# OpenTallas memory compiler (tools/mem_compiler), ASAP7 abstract view
VERSION 5.7 ;
BUSBITCHARS "[]" ;
DIVIDERCHAR "/" ;
PROPERTYDEFINITIONS
  MACRO width INTEGER ;
  MACRO depth INTEGER ;
  MACRO banks INTEGER ;
END PROPERTYDEFINITIONS
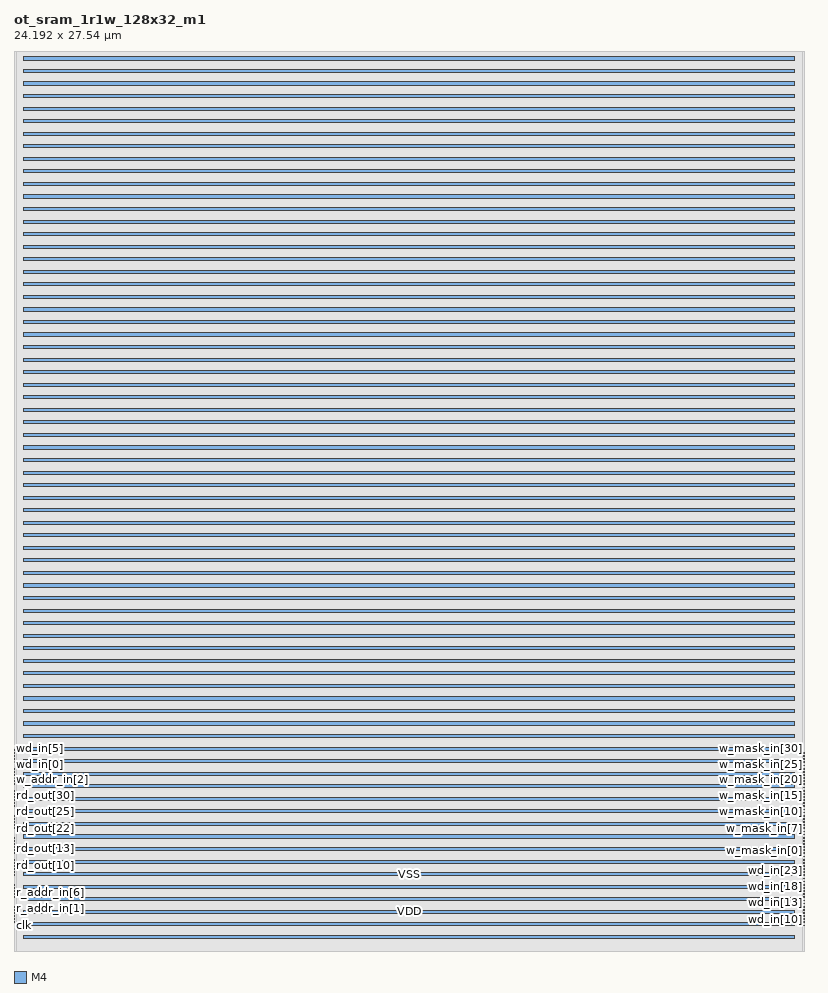
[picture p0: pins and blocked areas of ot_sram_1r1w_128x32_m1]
MACRO ot_sram_1r1w_128x32_m1
  PROPERTY width 32 ;
  PROPERTY depth 128 ;
  PROPERTY banks 1 ;
  FOREIGN ot_sram_1r1w_128x32_m1 0 0 ;
  SYMMETRY X Y R90 ;
  SIZE 24.192 BY 27.540 ;
  CLASS BLOCK ;
  PIN clk
    DIRECTION INPUT ;
    USE CLOCK ;
    SHAPE ABUTMENT ;
    PORT
      LAYER M4 ;
      RECT 0.000 0.768 0.024 0.792 ;
    END
  END clk
  PIN r_ce_in
    DIRECTION INPUT ;
    USE SIGNAL ;
    SHAPE ABUTMENT ;
    PORT
      LAYER M4 ;
      RECT 0.000 0.864 0.024 0.888 ;
    END
  END r_ce_in
  PIN r_addr_in[0]
    DIRECTION INPUT ;
    USE SIGNAL ;
    SHAPE ABUTMENT ;
    PORT
      LAYER M4 ;
      RECT 0.000 0.960 0.024 0.984 ;
    END
  END r_addr_in[0]
  PIN r_addr_in[1]
    DIRECTION INPUT ;
    USE SIGNAL ;
    SHAPE ABUTMENT ;
    PORT
      LAYER M4 ;
      RECT 0.000 1.056 0.024 1.080 ;
    END
  END r_addr_in[1]
  PIN r_addr_in[2]
    DIRECTION INPUT ;
    USE SIGNAL ;
    SHAPE ABUTMENT ;
    PORT
      LAYER M4 ;
      RECT 0.000 1.152 0.024 1.176 ;
    END
  END r_addr_in[2]
  PIN r_addr_in[3]
    DIRECTION INPUT ;
    USE SIGNAL ;
    SHAPE ABUTMENT ;
    PORT
      LAYER M4 ;
      RECT 0.000 1.248 0.024 1.272 ;
    END
  END r_addr_in[3]
  PIN r_addr_in[4]
    DIRECTION INPUT ;
    USE SIGNAL ;
    SHAPE ABUTMENT ;
    PORT
      LAYER M4 ;
      RECT 0.000 1.344 0.024 1.368 ;
    END
  END r_addr_in[4]
  PIN r_addr_in[5]
    DIRECTION INPUT ;
    USE SIGNAL ;
    SHAPE ABUTMENT ;
    PORT
      LAYER M4 ;
      RECT 0.000 1.440 0.024 1.464 ;
    END
  END r_addr_in[5]
  PIN r_addr_in[6]
    DIRECTION INPUT ;
    USE SIGNAL ;
    SHAPE ABUTMENT ;
    PORT
      LAYER M4 ;
      RECT 0.000 1.536 0.024 1.560 ;
    END
  END r_addr_in[6]
  PIN rd_out[0]
    DIRECTION OUTPUT ;
    USE SIGNAL ;
    SHAPE ABUTMENT ;
    PORT
      LAYER M4 ;
      RECT 0.000 1.632 0.024 1.656 ;
    END
  END rd_out[0]
  PIN rd_out[1]
    DIRECTION OUTPUT ;
    USE SIGNAL ;
    SHAPE ABUTMENT ;
    PORT
      LAYER M4 ;
      RECT 0.000 1.728 0.024 1.752 ;
    END
  END rd_out[1]
  PIN rd_out[2]
    DIRECTION OUTPUT ;
    USE SIGNAL ;
    SHAPE ABUTMENT ;
    PORT
      LAYER M4 ;
      RECT 0.000 1.824 0.024 1.848 ;
    END
  END rd_out[2]
  PIN rd_out[3]
    DIRECTION OUTPUT ;
    USE SIGNAL ;
    SHAPE ABUTMENT ;
    PORT
      LAYER M4 ;
      RECT 0.000 1.920 0.024 1.944 ;
    END
  END rd_out[3]
  PIN rd_out[4]
    DIRECTION OUTPUT ;
    USE SIGNAL ;
    SHAPE ABUTMENT ;
    PORT
      LAYER M4 ;
      RECT 0.000 2.016 0.024 2.040 ;
    END
  END rd_out[4]
  PIN rd_out[5]
    DIRECTION OUTPUT ;
    USE SIGNAL ;
    SHAPE ABUTMENT ;
    PORT
      LAYER M4 ;
      RECT 0.000 2.112 0.024 2.136 ;
    END
  END rd_out[5]
  PIN rd_out[6]
    DIRECTION OUTPUT ;
    USE SIGNAL ;
    SHAPE ABUTMENT ;
    PORT
      LAYER M4 ;
      RECT 0.000 2.208 0.024 2.232 ;
    END
  END rd_out[6]
  PIN rd_out[7]
    DIRECTION OUTPUT ;
    USE SIGNAL ;
    SHAPE ABUTMENT ;
    PORT
      LAYER M4 ;
      RECT 0.000 2.304 0.024 2.328 ;
    END
  END rd_out[7]
  PIN rd_out[8]
    DIRECTION OUTPUT ;
    USE SIGNAL ;
    SHAPE ABUTMENT ;
    PORT
      LAYER M4 ;
      RECT 0.000 2.400 0.024 2.424 ;
    END
  END rd_out[8]
  PIN rd_out[9]
    DIRECTION OUTPUT ;
    USE SIGNAL ;
    SHAPE ABUTMENT ;
    PORT
      LAYER M4 ;
      RECT 0.000 2.496 0.024 2.520 ;
    END
  END rd_out[9]
  PIN rd_out[10]
    DIRECTION OUTPUT ;
    USE SIGNAL ;
    SHAPE ABUTMENT ;
    PORT
      LAYER M4 ;
      RECT 0.000 2.592 0.024 2.616 ;
    END
  END rd_out[10]
  PIN rd_out[11]
    DIRECTION OUTPUT ;
    USE SIGNAL ;
    SHAPE ABUTMENT ;
    PORT
      LAYER M4 ;
      RECT 0.000 2.688 0.024 2.712 ;
    END
  END rd_out[11]
  PIN rd_out[12]
    DIRECTION OUTPUT ;
    USE SIGNAL ;
    SHAPE ABUTMENT ;
    PORT
      LAYER M4 ;
      RECT 0.000 2.784 0.024 2.808 ;
    END
  END rd_out[12]
  PIN rd_out[13]
    DIRECTION OUTPUT ;
    USE SIGNAL ;
    SHAPE ABUTMENT ;
    PORT
      LAYER M4 ;
      RECT 0.000 2.880 0.024 2.904 ;
    END
  END rd_out[13]
  PIN rd_out[14]
    DIRECTION OUTPUT ;
    USE SIGNAL ;
    SHAPE ABUTMENT ;
    PORT
      LAYER M4 ;
      RECT 0.000 2.976 0.024 3.000 ;
    END
  END rd_out[14]
  PIN rd_out[15]
    DIRECTION OUTPUT ;
    USE SIGNAL ;
    SHAPE ABUTMENT ;
    PORT
      LAYER M4 ;
      RECT 0.000 3.072 0.024 3.096 ;
    END
  END rd_out[15]
  PIN rd_out[16]
    DIRECTION OUTPUT ;
    USE SIGNAL ;
    SHAPE ABUTMENT ;
    PORT
      LAYER M4 ;
      RECT 0.000 3.168 0.024 3.192 ;
    END
  END rd_out[16]
  PIN rd_out[17]
    DIRECTION OUTPUT ;
    USE SIGNAL ;
    SHAPE ABUTMENT ;
    PORT
      LAYER M4 ;
      RECT 0.000 3.264 0.024 3.288 ;
    END
  END rd_out[17]
  PIN rd_out[18]
    DIRECTION OUTPUT ;
    USE SIGNAL ;
    SHAPE ABUTMENT ;
    PORT
      LAYER M4 ;
      RECT 0.000 3.360 0.024 3.384 ;
    END
  END rd_out[18]
  PIN rd_out[19]
    DIRECTION OUTPUT ;
    USE SIGNAL ;
    SHAPE ABUTMENT ;
    PORT
      LAYER M4 ;
      RECT 0.000 3.456 0.024 3.480 ;
    END
  END rd_out[19]
  PIN rd_out[20]
    DIRECTION OUTPUT ;
    USE SIGNAL ;
    SHAPE ABUTMENT ;
    PORT
      LAYER M4 ;
      RECT 0.000 3.552 0.024 3.576 ;
    END
  END rd_out[20]
  PIN rd_out[21]
    DIRECTION OUTPUT ;
    USE SIGNAL ;
    SHAPE ABUTMENT ;
    PORT
      LAYER M4 ;
      RECT 0.000 3.648 0.024 3.672 ;
    END
  END rd_out[21]
  PIN rd_out[22]
    DIRECTION OUTPUT ;
    USE SIGNAL ;
    SHAPE ABUTMENT ;
    PORT
      LAYER M4 ;
      RECT 0.000 3.744 0.024 3.768 ;
    END
  END rd_out[22]
  PIN rd_out[23]
    DIRECTION OUTPUT ;
    USE SIGNAL ;
    SHAPE ABUTMENT ;
    PORT
      LAYER M4 ;
      RECT 0.000 3.840 0.024 3.864 ;
    END
  END rd_out[23]
  PIN rd_out[24]
    DIRECTION OUTPUT ;
    USE SIGNAL ;
    SHAPE ABUTMENT ;
    PORT
      LAYER M4 ;
      RECT 0.000 3.936 0.024 3.960 ;
    END
  END rd_out[24]
  PIN rd_out[25]
    DIRECTION OUTPUT ;
    USE SIGNAL ;
    SHAPE ABUTMENT ;
    PORT
      LAYER M4 ;
      RECT 0.000 4.032 0.024 4.056 ;
    END
  END rd_out[25]
  PIN rd_out[26]
    DIRECTION OUTPUT ;
    USE SIGNAL ;
    SHAPE ABUTMENT ;
    PORT
      LAYER M4 ;
      RECT 0.000 4.128 0.024 4.152 ;
    END
  END rd_out[26]
  PIN rd_out[27]
    DIRECTION OUTPUT ;
    USE SIGNAL ;
    SHAPE ABUTMENT ;
    PORT
      LAYER M4 ;
      RECT 0.000 4.224 0.024 4.248 ;
    END
  END rd_out[27]
  PIN rd_out[28]
    DIRECTION OUTPUT ;
    USE SIGNAL ;
    SHAPE ABUTMENT ;
    PORT
      LAYER M4 ;
      RECT 0.000 4.320 0.024 4.344 ;
    END
  END rd_out[28]
  PIN rd_out[29]
    DIRECTION OUTPUT ;
    USE SIGNAL ;
    SHAPE ABUTMENT ;
    PORT
      LAYER M4 ;
      RECT 0.000 4.416 0.024 4.440 ;
    END
  END rd_out[29]
  PIN rd_out[30]
    DIRECTION OUTPUT ;
    USE SIGNAL ;
    SHAPE ABUTMENT ;
    PORT
      LAYER M4 ;
      RECT 0.000 4.512 0.024 4.536 ;
    END
  END rd_out[30]
  PIN rd_out[31]
    DIRECTION OUTPUT ;
    USE SIGNAL ;
    SHAPE ABUTMENT ;
    PORT
      LAYER M4 ;
      RECT 0.000 4.608 0.024 4.632 ;
    END
  END rd_out[31]
  PIN w_ce_in
    DIRECTION INPUT ;
    USE SIGNAL ;
    SHAPE ABUTMENT ;
    PORT
      LAYER M4 ;
      RECT 0.000 4.704 0.024 4.728 ;
    END
  END w_ce_in
  PIN w_addr_in[0]
    DIRECTION INPUT ;
    USE SIGNAL ;
    SHAPE ABUTMENT ;
    PORT
      LAYER M4 ;
      RECT 0.000 4.800 0.024 4.824 ;
    END
  END w_addr_in[0]
  PIN w_addr_in[1]
    DIRECTION INPUT ;
    USE SIGNAL ;
    SHAPE ABUTMENT ;
    PORT
      LAYER M4 ;
      RECT 0.000 4.896 0.024 4.920 ;
    END
  END w_addr_in[1]
  PIN w_addr_in[2]
    DIRECTION INPUT ;
    USE SIGNAL ;
    SHAPE ABUTMENT ;
    PORT
      LAYER M4 ;
      RECT 0.000 4.992 0.024 5.016 ;
    END
  END w_addr_in[2]
  PIN w_addr_in[3]
    DIRECTION INPUT ;
    USE SIGNAL ;
    SHAPE ABUTMENT ;
    PORT
      LAYER M4 ;
      RECT 0.000 5.088 0.024 5.112 ;
    END
  END w_addr_in[3]
  PIN w_addr_in[4]
    DIRECTION INPUT ;
    USE SIGNAL ;
    SHAPE ABUTMENT ;
    PORT
      LAYER M4 ;
      RECT 0.000 5.184 0.024 5.208 ;
    END
  END w_addr_in[4]
  PIN w_addr_in[5]
    DIRECTION INPUT ;
    USE SIGNAL ;
    SHAPE ABUTMENT ;
    PORT
      LAYER M4 ;
      RECT 0.000 5.280 0.024 5.304 ;
    END
  END w_addr_in[5]
  PIN w_addr_in[6]
    DIRECTION INPUT ;
    USE SIGNAL ;
    SHAPE ABUTMENT ;
    PORT
      LAYER M4 ;
      RECT 0.000 5.376 0.024 5.400 ;
    END
  END w_addr_in[6]
  PIN wd_in[0]
    DIRECTION INPUT ;
    USE SIGNAL ;
    SHAPE ABUTMENT ;
    PORT
      LAYER M4 ;
      RECT 0.000 5.472 0.024 5.496 ;
    END
  END wd_in[0]
  PIN wd_in[1]
    DIRECTION INPUT ;
    USE SIGNAL ;
    SHAPE ABUTMENT ;
    PORT
      LAYER M4 ;
      RECT 0.000 5.568 0.024 5.592 ;
    END
  END wd_in[1]
  PIN wd_in[2]
    DIRECTION INPUT ;
    USE SIGNAL ;
    SHAPE ABUTMENT ;
    PORT
      LAYER M4 ;
      RECT 0.000 5.664 0.024 5.688 ;
    END
  END wd_in[2]
  PIN wd_in[3]
    DIRECTION INPUT ;
    USE SIGNAL ;
    SHAPE ABUTMENT ;
    PORT
      LAYER M4 ;
      RECT 0.000 5.760 0.024 5.784 ;
    END
  END wd_in[3]
  PIN wd_in[4]
    DIRECTION INPUT ;
    USE SIGNAL ;
    SHAPE ABUTMENT ;
    PORT
      LAYER M4 ;
      RECT 0.000 5.856 0.024 5.880 ;
    END
  END wd_in[4]
  PIN wd_in[5]
    DIRECTION INPUT ;
    USE SIGNAL ;
    SHAPE ABUTMENT ;
    PORT
      LAYER M4 ;
      RECT 0.000 5.952 0.024 5.976 ;
    END
  END wd_in[5]
  PIN wd_in[6]
    DIRECTION INPUT ;
    USE SIGNAL ;
    SHAPE ABUTMENT ;
    PORT
      LAYER M4 ;
      RECT 0.000 6.048 0.024 6.072 ;
    END
  END wd_in[6]
  PIN wd_in[7]
    DIRECTION INPUT ;
    USE SIGNAL ;
    SHAPE ABUTMENT ;
    PORT
      LAYER M4 ;
      RECT 0.000 6.144 0.024 6.168 ;
    END
  END wd_in[7]
  PIN wd_in[8]
    DIRECTION INPUT ;
    USE SIGNAL ;
    SHAPE ABUTMENT ;
    PORT
      LAYER M4 ;
      RECT 24.168 0.768 24.192 0.792 ;
    END
  END wd_in[8]
  PIN wd_in[9]
    DIRECTION INPUT ;
    USE SIGNAL ;
    SHAPE ABUTMENT ;
    PORT
      LAYER M4 ;
      RECT 24.168 0.864 24.192 0.888 ;
    END
  END wd_in[9]
  PIN wd_in[10]
    DIRECTION INPUT ;
    USE SIGNAL ;
    SHAPE ABUTMENT ;
    PORT
      LAYER M4 ;
      RECT 24.168 0.960 24.192 0.984 ;
    END
  END wd_in[10]
  PIN wd_in[11]
    DIRECTION INPUT ;
    USE SIGNAL ;
    SHAPE ABUTMENT ;
    PORT
      LAYER M4 ;
      RECT 24.168 1.056 24.192 1.080 ;
    END
  END wd_in[11]
  PIN wd_in[12]
    DIRECTION INPUT ;
    USE SIGNAL ;
    SHAPE ABUTMENT ;
    PORT
      LAYER M4 ;
      RECT 24.168 1.152 24.192 1.176 ;
    END
  END wd_in[12]
  PIN wd_in[13]
    DIRECTION INPUT ;
    USE SIGNAL ;
    SHAPE ABUTMENT ;
    PORT
      LAYER M4 ;
      RECT 24.168 1.248 24.192 1.272 ;
    END
  END wd_in[13]
  PIN wd_in[14]
    DIRECTION INPUT ;
    USE SIGNAL ;
    SHAPE ABUTMENT ;
    PORT
      LAYER M4 ;
      RECT 24.168 1.344 24.192 1.368 ;
    END
  END wd_in[14]
  PIN wd_in[15]
    DIRECTION INPUT ;
    USE SIGNAL ;
    SHAPE ABUTMENT ;
    PORT
      LAYER M4 ;
      RECT 24.168 1.440 24.192 1.464 ;
    END
  END wd_in[15]
  PIN wd_in[16]
    DIRECTION INPUT ;
    USE SIGNAL ;
    SHAPE ABUTMENT ;
    PORT
      LAYER M4 ;
      RECT 24.168 1.536 24.192 1.560 ;
    END
  END wd_in[16]
  PIN wd_in[17]
    DIRECTION INPUT ;
    USE SIGNAL ;
    SHAPE ABUTMENT ;
    PORT
      LAYER M4 ;
      RECT 24.168 1.632 24.192 1.656 ;
    END
  END wd_in[17]
  PIN wd_in[18]
    DIRECTION INPUT ;
    USE SIGNAL ;
    SHAPE ABUTMENT ;
    PORT
      LAYER M4 ;
      RECT 24.168 1.728 24.192 1.752 ;
    END
  END wd_in[18]
  PIN wd_in[19]
    DIRECTION INPUT ;
    USE SIGNAL ;
    SHAPE ABUTMENT ;
    PORT
      LAYER M4 ;
      RECT 24.168 1.824 24.192 1.848 ;
    END
  END wd_in[19]
  PIN wd_in[20]
    DIRECTION INPUT ;
    USE SIGNAL ;
    SHAPE ABUTMENT ;
    PORT
      LAYER M4 ;
      RECT 24.168 1.920 24.192 1.944 ;
    END
  END wd_in[20]
  PIN wd_in[21]
    DIRECTION INPUT ;
    USE SIGNAL ;
    SHAPE ABUTMENT ;
    PORT
      LAYER M4 ;
      RECT 24.168 2.016 24.192 2.040 ;
    END
  END wd_in[21]
  PIN wd_in[22]
    DIRECTION INPUT ;
    USE SIGNAL ;
    SHAPE ABUTMENT ;
    PORT
      LAYER M4 ;
      RECT 24.168 2.112 24.192 2.136 ;
    END
  END wd_in[22]
  PIN wd_in[23]
    DIRECTION INPUT ;
    USE SIGNAL ;
    SHAPE ABUTMENT ;
    PORT
      LAYER M4 ;
      RECT 24.168 2.208 24.192 2.232 ;
    END
  END wd_in[23]
  PIN wd_in[24]
    DIRECTION INPUT ;
    USE SIGNAL ;
    SHAPE ABUTMENT ;
    PORT
      LAYER M4 ;
      RECT 24.168 2.304 24.192 2.328 ;
    END
  END wd_in[24]
  PIN wd_in[25]
    DIRECTION INPUT ;
    USE SIGNAL ;
    SHAPE ABUTMENT ;
    PORT
      LAYER M4 ;
      RECT 24.168 2.400 24.192 2.424 ;
    END
  END wd_in[25]
  PIN wd_in[26]
    DIRECTION INPUT ;
    USE SIGNAL ;
    SHAPE ABUTMENT ;
    PORT
      LAYER M4 ;
      RECT 24.168 2.496 24.192 2.520 ;
    END
  END wd_in[26]
  PIN wd_in[27]
    DIRECTION INPUT ;
    USE SIGNAL ;
    SHAPE ABUTMENT ;
    PORT
      LAYER M4 ;
      RECT 24.168 2.592 24.192 2.616 ;
    END
  END wd_in[27]
  PIN wd_in[28]
    DIRECTION INPUT ;
    USE SIGNAL ;
    SHAPE ABUTMENT ;
    PORT
      LAYER M4 ;
      RECT 24.168 2.688 24.192 2.712 ;
    END
  END wd_in[28]
  PIN wd_in[29]
    DIRECTION INPUT ;
    USE SIGNAL ;
    SHAPE ABUTMENT ;
    PORT
      LAYER M4 ;
      RECT 24.168 2.784 24.192 2.808 ;
    END
  END wd_in[29]
  PIN wd_in[30]
    DIRECTION INPUT ;
    USE SIGNAL ;
    SHAPE ABUTMENT ;
    PORT
      LAYER M4 ;
      RECT 24.168 2.880 24.192 2.904 ;
    END
  END wd_in[30]
  PIN wd_in[31]
    DIRECTION INPUT ;
    USE SIGNAL ;
    SHAPE ABUTMENT ;
    PORT
      LAYER M4 ;
      RECT 24.168 2.976 24.192 3.000 ;
    END
  END wd_in[31]
  PIN w_mask_in[0]
    DIRECTION INPUT ;
    USE SIGNAL ;
    SHAPE ABUTMENT ;
    PORT
      LAYER M4 ;
      RECT 24.168 3.072 24.192 3.096 ;
    END
  END w_mask_in[0]
  PIN w_mask_in[1]
    DIRECTION INPUT ;
    USE SIGNAL ;
    SHAPE ABUTMENT ;
    PORT
      LAYER M4 ;
      RECT 24.168 3.168 24.192 3.192 ;
    END
  END w_mask_in[1]
  PIN w_mask_in[2]
    DIRECTION INPUT ;
    USE SIGNAL ;
    SHAPE ABUTMENT ;
    PORT
      LAYER M4 ;
      RECT 24.168 3.264 24.192 3.288 ;
    END
  END w_mask_in[2]
  PIN w_mask_in[3]
    DIRECTION INPUT ;
    USE SIGNAL ;
    SHAPE ABUTMENT ;
    PORT
      LAYER M4 ;
      RECT 24.168 3.360 24.192 3.384 ;
    END
  END w_mask_in[3]
  PIN w_mask_in[4]
    DIRECTION INPUT ;
    USE SIGNAL ;
    SHAPE ABUTMENT ;
    PORT
      LAYER M4 ;
      RECT 24.168 3.456 24.192 3.480 ;
    END
  END w_mask_in[4]
  PIN w_mask_in[5]
    DIRECTION INPUT ;
    USE SIGNAL ;
    SHAPE ABUTMENT ;
    PORT
      LAYER M4 ;
      RECT 24.168 3.552 24.192 3.576 ;
    END
  END w_mask_in[5]
  PIN w_mask_in[6]
    DIRECTION INPUT ;
    USE SIGNAL ;
    SHAPE ABUTMENT ;
    PORT
      LAYER M4 ;
      RECT 24.168 3.648 24.192 3.672 ;
    END
  END w_mask_in[6]
  PIN w_mask_in[7]
    DIRECTION INPUT ;
    USE SIGNAL ;
    SHAPE ABUTMENT ;
    PORT
      LAYER M4 ;
      RECT 24.168 3.744 24.192 3.768 ;
    END
  END w_mask_in[7]
  PIN w_mask_in[8]
    DIRECTION INPUT ;
    USE SIGNAL ;
    SHAPE ABUTMENT ;
    PORT
      LAYER M4 ;
      RECT 24.168 3.840 24.192 3.864 ;
    END
  END w_mask_in[8]
  PIN w_mask_in[9]
    DIRECTION INPUT ;
    USE SIGNAL ;
    SHAPE ABUTMENT ;
    PORT
      LAYER M4 ;
      RECT 24.168 3.936 24.192 3.960 ;
    END
  END w_mask_in[9]
  PIN w_mask_in[10]
    DIRECTION INPUT ;
    USE SIGNAL ;
    SHAPE ABUTMENT ;
    PORT
      LAYER M4 ;
      RECT 24.168 4.032 24.192 4.056 ;
    END
  END w_mask_in[10]
  PIN w_mask_in[11]
    DIRECTION INPUT ;
    USE SIGNAL ;
    SHAPE ABUTMENT ;
    PORT
      LAYER M4 ;
      RECT 24.168 4.128 24.192 4.152 ;
    END
  END w_mask_in[11]
  PIN w_mask_in[12]
    DIRECTION INPUT ;
    USE SIGNAL ;
    SHAPE ABUTMENT ;
    PORT
      LAYER M4 ;
      RECT 24.168 4.224 24.192 4.248 ;
    END
  END w_mask_in[12]
  PIN w_mask_in[13]
    DIRECTION INPUT ;
    USE SIGNAL ;
    SHAPE ABUTMENT ;
    PORT
      LAYER M4 ;
      RECT 24.168 4.320 24.192 4.344 ;
    END
  END w_mask_in[13]
  PIN w_mask_in[14]
    DIRECTION INPUT ;
    USE SIGNAL ;
    SHAPE ABUTMENT ;
    PORT
      LAYER M4 ;
      RECT 24.168 4.416 24.192 4.440 ;
    END
  END w_mask_in[14]
  PIN w_mask_in[15]
    DIRECTION INPUT ;
    USE SIGNAL ;
    SHAPE ABUTMENT ;
    PORT
      LAYER M4 ;
      RECT 24.168 4.512 24.192 4.536 ;
    END
  END w_mask_in[15]
  PIN w_mask_in[16]
    DIRECTION INPUT ;
    USE SIGNAL ;
    SHAPE ABUTMENT ;
    PORT
      LAYER M4 ;
      RECT 24.168 4.608 24.192 4.632 ;
    END
  END w_mask_in[16]
  PIN w_mask_in[17]
    DIRECTION INPUT ;
    USE SIGNAL ;
    SHAPE ABUTMENT ;
    PORT
      LAYER M4 ;
      RECT 24.168 4.704 24.192 4.728 ;
    END
  END w_mask_in[17]
  PIN w_mask_in[18]
    DIRECTION INPUT ;
    USE SIGNAL ;
    SHAPE ABUTMENT ;
    PORT
      LAYER M4 ;
      RECT 24.168 4.800 24.192 4.824 ;
    END
  END w_mask_in[18]
  PIN w_mask_in[19]
    DIRECTION INPUT ;
    USE SIGNAL ;
    SHAPE ABUTMENT ;
    PORT
      LAYER M4 ;
      RECT 24.168 4.896 24.192 4.920 ;
    END
  END w_mask_in[19]
  PIN w_mask_in[20]
    DIRECTION INPUT ;
    USE SIGNAL ;
    SHAPE ABUTMENT ;
    PORT
      LAYER M4 ;
      RECT 24.168 4.992 24.192 5.016 ;
    END
  END w_mask_in[20]
  PIN w_mask_in[21]
    DIRECTION INPUT ;
    USE SIGNAL ;
    SHAPE ABUTMENT ;
    PORT
      LAYER M4 ;
      RECT 24.168 5.088 24.192 5.112 ;
    END
  END w_mask_in[21]
  PIN w_mask_in[22]
    DIRECTION INPUT ;
    USE SIGNAL ;
    SHAPE ABUTMENT ;
    PORT
      LAYER M4 ;
      RECT 24.168 5.184 24.192 5.208 ;
    END
  END w_mask_in[22]
  PIN w_mask_in[23]
    DIRECTION INPUT ;
    USE SIGNAL ;
    SHAPE ABUTMENT ;
    PORT
      LAYER M4 ;
      RECT 24.168 5.280 24.192 5.304 ;
    END
  END w_mask_in[23]
  PIN w_mask_in[24]
    DIRECTION INPUT ;
    USE SIGNAL ;
    SHAPE ABUTMENT ;
    PORT
      LAYER M4 ;
      RECT 24.168 5.376 24.192 5.400 ;
    END
  END w_mask_in[24]
  PIN w_mask_in[25]
    DIRECTION INPUT ;
    USE SIGNAL ;
    SHAPE ABUTMENT ;
    PORT
      LAYER M4 ;
      RECT 24.168 5.472 24.192 5.496 ;
    END
  END w_mask_in[25]
  PIN w_mask_in[26]
    DIRECTION INPUT ;
    USE SIGNAL ;
    SHAPE ABUTMENT ;
    PORT
      LAYER M4 ;
      RECT 24.168 5.568 24.192 5.592 ;
    END
  END w_mask_in[26]
  PIN w_mask_in[27]
    DIRECTION INPUT ;
    USE SIGNAL ;
    SHAPE ABUTMENT ;
    PORT
      LAYER M4 ;
      RECT 24.168 5.664 24.192 5.688 ;
    END
  END w_mask_in[27]
  PIN w_mask_in[28]
    DIRECTION INPUT ;
    USE SIGNAL ;
    SHAPE ABUTMENT ;
    PORT
      LAYER M4 ;
      RECT 24.168 5.760 24.192 5.784 ;
    END
  END w_mask_in[28]
  PIN w_mask_in[29]
    DIRECTION INPUT ;
    USE SIGNAL ;
    SHAPE ABUTMENT ;
    PORT
      LAYER M4 ;
      RECT 24.168 5.856 24.192 5.880 ;
    END
  END w_mask_in[29]
  PIN w_mask_in[30]
    DIRECTION INPUT ;
    USE SIGNAL ;
    SHAPE ABUTMENT ;
    PORT
      LAYER M4 ;
      RECT 24.168 5.952 24.192 5.976 ;
    END
  END w_mask_in[30]
  PIN w_mask_in[31]
    DIRECTION INPUT ;
    USE SIGNAL ;
    SHAPE ABUTMENT ;
    PORT
      LAYER M4 ;
      RECT 24.168 6.048 24.192 6.072 ;
    END
  END w_mask_in[31]
  PIN VDD
    DIRECTION INOUT ;
    USE POWER ;
    PORT
      LAYER M4 ;
      RECT 0.300 0.384 23.892 0.480 ;
      RECT 0.300 1.152 23.892 1.248 ;
      RECT 0.300 1.920 23.892 2.016 ;
      RECT 0.300 2.688 23.892 2.784 ;
      RECT 0.300 3.456 23.892 3.552 ;
      RECT 0.300 4.224 23.892 4.320 ;
      RECT 0.300 4.992 23.892 5.088 ;
      RECT 0.300 5.760 23.892 5.856 ;
      RECT 0.300 6.528 23.892 6.624 ;
      RECT 0.300 7.296 23.892 7.392 ;
      RECT 0.300 8.064 23.892 8.160 ;
      RECT 0.300 8.832 23.892 8.928 ;
      RECT 0.300 9.600 23.892 9.696 ;
      RECT 0.300 10.368 23.892 10.464 ;
      RECT 0.300 11.136 23.892 11.232 ;
      RECT 0.300 11.904 23.892 12.000 ;
      RECT 0.300 12.672 23.892 12.768 ;
      RECT 0.300 13.440 23.892 13.536 ;
      RECT 0.300 14.208 23.892 14.304 ;
      RECT 0.300 14.976 23.892 15.072 ;
      RECT 0.300 15.744 23.892 15.840 ;
      RECT 0.300 16.512 23.892 16.608 ;
      RECT 0.300 17.280 23.892 17.376 ;
      RECT 0.300 18.048 23.892 18.144 ;
      RECT 0.300 18.816 23.892 18.912 ;
      RECT 0.300 19.584 23.892 19.680 ;
      RECT 0.300 20.352 23.892 20.448 ;
      RECT 0.300 21.120 23.892 21.216 ;
      RECT 0.300 21.888 23.892 21.984 ;
      RECT 0.300 22.656 23.892 22.752 ;
      RECT 0.300 23.424 23.892 23.520 ;
      RECT 0.300 24.192 23.892 24.288 ;
      RECT 0.300 24.960 23.892 25.056 ;
      RECT 0.300 25.728 23.892 25.824 ;
      RECT 0.300 26.496 23.892 26.592 ;
      RECT 0.300 27.264 23.892 27.360 ;
    END
  END VDD
  PIN VSS
    DIRECTION INOUT ;
    USE GROUND ;
    PORT
      LAYER M4 ;
      RECT 0.300 0.768 23.892 0.864 ;
      RECT 0.300 1.536 23.892 1.632 ;
      RECT 0.300 2.304 23.892 2.400 ;
      RECT 0.300 3.072 23.892 3.168 ;
      RECT 0.300 3.840 23.892 3.936 ;
      RECT 0.300 4.608 23.892 4.704 ;
      RECT 0.300 5.376 23.892 5.472 ;
      RECT 0.300 6.144 23.892 6.240 ;
      RECT 0.300 6.912 23.892 7.008 ;
      RECT 0.300 7.680 23.892 7.776 ;
      RECT 0.300 8.448 23.892 8.544 ;
      RECT 0.300 9.216 23.892 9.312 ;
      RECT 0.300 9.984 23.892 10.080 ;
      RECT 0.300 10.752 23.892 10.848 ;
      RECT 0.300 11.520 23.892 11.616 ;
      RECT 0.300 12.288 23.892 12.384 ;
      RECT 0.300 13.056 23.892 13.152 ;
      RECT 0.300 13.824 23.892 13.920 ;
      RECT 0.300 14.592 23.892 14.688 ;
      RECT 0.300 15.360 23.892 15.456 ;
      RECT 0.300 16.128 23.892 16.224 ;
      RECT 0.300 16.896 23.892 16.992 ;
      RECT 0.300 17.664 23.892 17.760 ;
      RECT 0.300 18.432 23.892 18.528 ;
      RECT 0.300 19.200 23.892 19.296 ;
      RECT 0.300 19.968 23.892 20.064 ;
      RECT 0.300 20.736 23.892 20.832 ;
      RECT 0.300 21.504 23.892 21.600 ;
      RECT 0.300 22.272 23.892 22.368 ;
      RECT 0.300 23.040 23.892 23.136 ;
      RECT 0.300 23.808 23.892 23.904 ;
      RECT 0.300 24.576 23.892 24.672 ;
      RECT 0.300 25.344 23.892 25.440 ;
      RECT 0.300 26.112 23.892 26.208 ;
      RECT 0.300 26.880 23.892 26.976 ;
    END
  END VSS
  OBS
    LAYER M1 ;
    RECT 0 0 24.192 27.540 ;
    LAYER M2 ;
    RECT 0 0 24.192 27.540 ;
    LAYER M3 ;
    RECT 0 0 24.192 27.540 ;
    LAYER M4 ;
    RECT 0.072 0 24.120 27.540 ;
  END
END ot_sram_1r1w_128x32_m1

END LIBRARY
